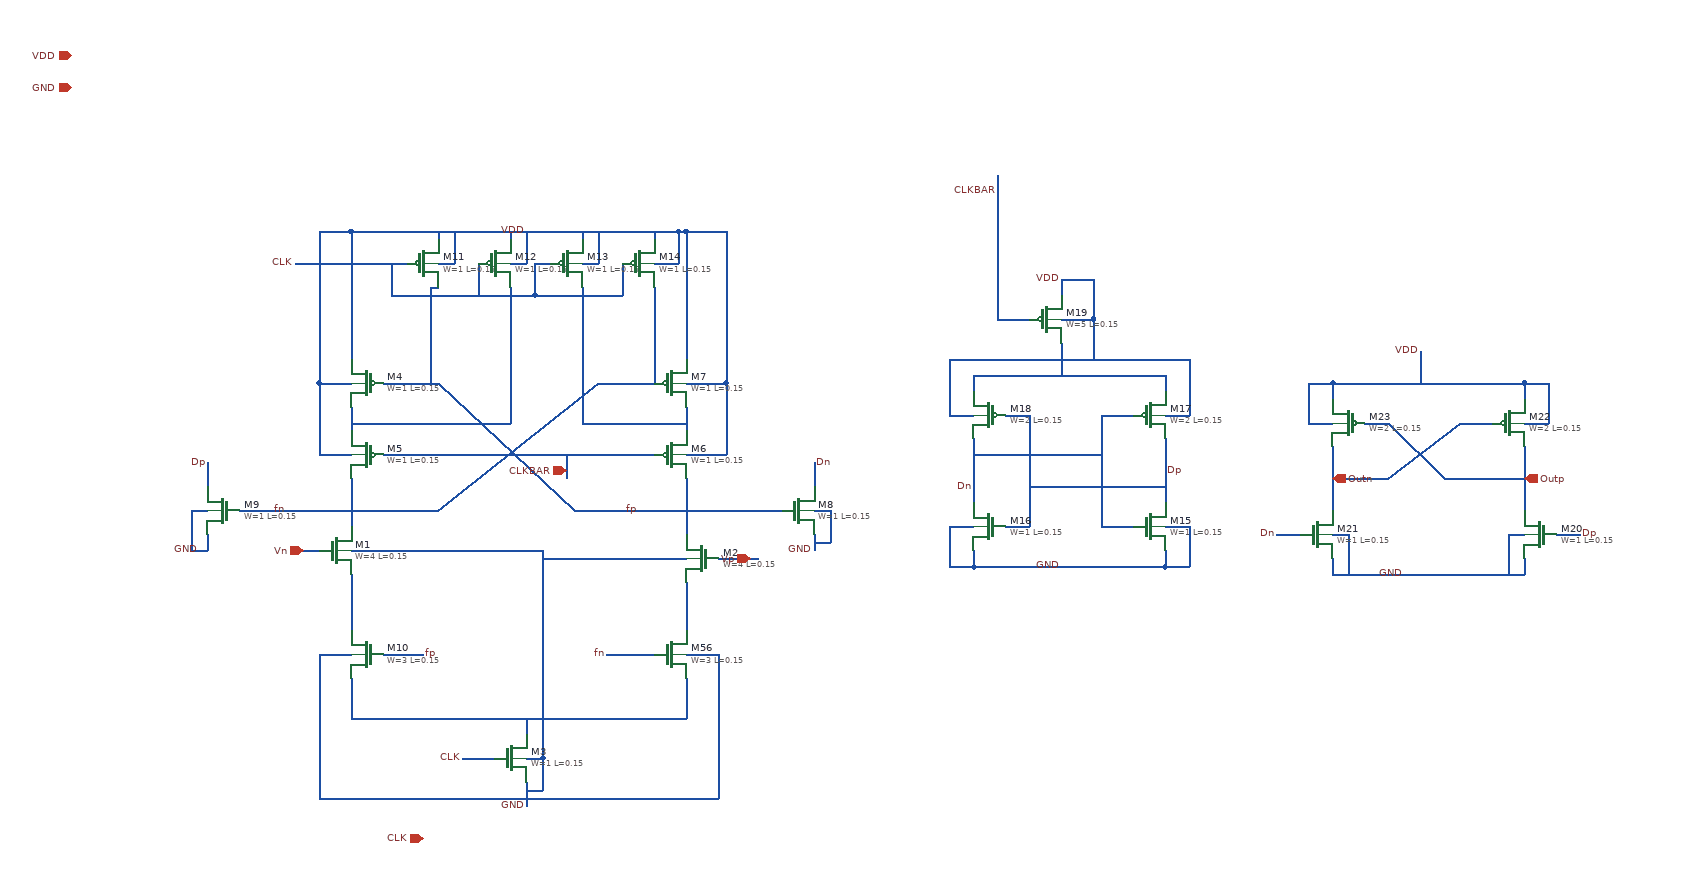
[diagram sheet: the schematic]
v {xschem version=3.0.0 file_version=1.2 }
G {}
K {}
V {}
S {}
E {}
N 1370 -860 1370 -820 {
lab=#net1}
N 1370 -680 1790 -680 {
lab=#net2}
N 1790 -850 1790 -820 {
lab=#net3}
N 1590 -680 1590 -660 {
lab=#net2}
N 1590 -600 1590 -570 {
lab=GND}
N 1590 -630 1610 -630 {
lab=GND}
N 1610 -630 1610 -590 {
lab=GND}
N 1590 -590 1610 -590 {
lab=GND}
N 1370 -890 1560 -890 {
lab=GND}
N 1610 -880 1790 -880 {
lab=GND}
N 1170 -940 1190 -940 {
lab=GND}
N 1170 -940 1170 -890 {
lab=GND}
N 1170 -890 1190 -890 {
lab=GND}
N 1190 -910 1190 -890 {
lab=GND}
N 1190 -1000 1190 -970 {
lab=Dp}
N 1340 -1250 1380 -1250 {
lab=CLK}
N 1530 -1250 1530 -1210 {
lab=CLK}
N 1420 -1250 1420 -1210 {
lab=CLK}
N 1600 -1250 1620 -1250 {
lab=CLK}
N 1600 -1250 1600 -1210 {
lab=CLK}
N 1480 -1210 1600 -1210 {
lab=CLK}
N 1600 -1210 1710 -1210 {
lab=CLK}
N 1420 -1290 1440 -1290 {
lab=VDD}
N 1440 -1290 1760 -1290 {
lab=VDD}
N 1660 -1290 1660 -1280 {
lab=VDD}
N 1570 -1290 1570 -1280 {
lab=VDD}
N 1570 -1250 1580 -1250 {
lab=VDD}
N 1580 -1250 1590 -1250 {
lab=VDD}
N 1590 -1290 1590 -1250 {
lab=VDD}
N 1660 -1250 1680 -1250 {
lab=VDD}
N 1680 -1290 1680 -1250 {
lab=VDD}
N 1760 -1250 1780 -1250 {
lab=VDD}
N 1780 -1290 1780 -1250 {
lab=VDD}
N 1760 -1290 1780 -1290 {
lab=VDD}
N 1510 -630 1550 -630 {
lab=CLK}
N 1300 -890 1330 -890 {
lab=Vn}
N 1830 -880 1880 -880 {
lab=Vp}
N 2190 -1060 2220 -1060 {
lab=Dp}
N 2220 -1060 2220 -920 {
lab=Dp}
N 2190 -920 2220 -920 {
lab=Dp}
N 2310 -1060 2350 -1060 {
lab=Dn}
N 2310 -1060 2310 -920 {
lab=Dn}
N 2150 -1030 2150 -950 {
lab=Dn}
N 2310 -920 2350 -920 {
lab=Dn}
N 2390 -1030 2390 -950 {
lab=Dp}
N 2150 -890 2150 -870 {
lab=GND}
N 2150 -870 2390 -870 {
lab=GND}
N 2390 -890 2390 -870 {
lab=GND}
N 2150 -1110 2150 -1090 {
lab=#net4}
N 2150 -1110 2390 -1110 {
lab=#net4}
N 2390 -1110 2390 -1090 {
lab=#net4}
N 2150 -1010 2310 -1010 {
lab=Dn}
N 2220 -970 2390 -970 {
lab=Dp}
N 2120 -920 2150 -920 {
lab=GND}
N 2120 -920 2120 -870 {
lab=GND}
N 2120 -870 2150 -870 {
lab=GND}
N 2390 -920 2410 -920 {
lab=GND}
N 2410 -920 2420 -920 {
lab=GND}
N 2420 -920 2420 -870 {
lab=GND}
N 2390 -870 2420 -870 {
lab=GND}
N 2260 -1150 2260 -1110 {
lab=#net4}
N 2260 -1180 2300 -1180 {
lab=VDD}
N 2300 -1230 2300 -1180 {
lab=VDD}
N 2260 -1230 2300 -1230 {
lab=VDD}
N 2260 -1230 2260 -1210 {
lab=VDD}
N 2120 -1060 2150 -1060 {
lab=VDD}
N 2120 -1110 2120 -1060 {
lab=VDD}
N 2390 -1060 2420 -1060 {
lab=VDD}
N 2420 -1110 2420 -1060 {
lab=VDD}
N 2190 -1180 2220 -1180 {
lab=CLKBAR}
N 2640 -1050 2670 -1050 {
lab=Outp}
N 2760 -1050 2800 -1050 {
lab=Outp}
N 2600 -1020 2600 -940 {
lab=Outp}
N 2840 -1020 2840 -940 {
lab=Outp}
N 2600 -880 2600 -860 {
lab=GND}
N 2600 -860 2840 -860 {
lab=GND}
N 2840 -880 2840 -860 {
lab=GND}
N 2600 -1100 2600 -1080 {
lab=VDD}
N 2600 -1100 2840 -1100 {
lab=VDD}
N 2840 -1100 2840 -1080 {
lab=VDD}
N 2710 -1140 2710 -1100 {
lab=VDD}
N 2570 -1050 2600 -1050 {
lab=VDD}
N 2570 -1100 2570 -1050 {
lab=VDD}
N 2570 -1100 2600 -1100 {
lab=VDD}
N 2840 -1050 2870 -1050 {
lab=VDD}
N 2870 -1100 2870 -1050 {
lab=VDD}
N 2840 -1100 2870 -1100 {
lab=VDD}
N 2530 -910 2560 -910 {
lab=Dn}
N 2880 -910 2910 -910 {
lab=Dp}
N 2670 -1050 2740 -980 {
lab=Outp}
N 2740 -980 2840 -980 {
lab=Outp}
N 2670 -980 2760 -1050 {
lab=Outp}
N 2600 -980 2670 -980 {
lab=Outp}
N 2600 -910 2620 -910 {
lab=GND}
N 2620 -910 2620 -860 {
lab=GND}
N 2820 -910 2840 -910 {
lab=GND}
N 2820 -910 2820 -860 {
lab=GND}
N 2120 -1130 2120 -1110 {
lab=VDD}
N 2120 -1130 2420 -1130 {
lab=VDD}
N 2420 -1130 2420 -1110 {
lab=VDD}
N 2300 -1180 2300 -1130 {
lab=VDD}
N 2180 -1360 2180 -1180 {
lab=CLKBAR}
N 2180 -1180 2190 -1180 {
lab=CLKBAR}
N 1610 -880 1610 -770 {
lab=GND}
N 1560 -890 1610 -890 {
lab=GND}
N 1610 -890 1610 -870 {
lab=GND}
N 1370 -980 1370 -920 {
lab=fn}
N 1370 -1070 1370 -1040 {
lab=#net5}
N 1790 -980 1790 -910 {
lab=fp}
N 1790 -1070 1790 -1040 {
lab=#net6}
N 1370 -1150 1370 -1130 {
lab=VDD}
N 1790 -1150 1790 -1130 {
lab=VDD}
N 1410 -1010 1750 -1010 {
lab=CLKBAR}
N 1410 -1100 1480 -1100 {
lab=fp}
N 1480 -1100 1650 -940 {
lab=fp}
N 1650 -940 1790 -940 {
lab=fp}
N 1680 -1100 1750 -1100 {
lab=fn}
N 1480 -940 1680 -1100 {
lab=fn}
N 1370 -940 1480 -940 {
lab=fn}
N 1370 -1160 1370 -1150 {
lab=VDD}
N 1790 -1160 1790 -1150 {
lab=VDD}
N 1750 -1290 1750 -1280 {
lab=VDD}
N 1750 -1250 1760 -1250 {
lab=VDD}
N 1710 -1250 1710 -1210 {
lab=CLK}
N 1750 -1220 1750 -1100 {
lab=fn}
N 1370 -1050 1520 -1050 {
lab=#net5}
N 1570 -1220 1570 -1050 {
lab=#net5}
N 1660 -1220 1660 -1050 {
lab=#net6}
N 1660 -1050 1790 -1050 {
lab=#net6}
N 1230 -940 1370 -940 {
lab=fn}
N 1950 -910 1950 -890 {
lab=GND}
N 1950 -940 1970 -940 {
lab=GND}
N 1970 -940 1970 -900 {
lab=GND}
N 1950 -900 1970 -900 {
lab=GND}
N 1950 -990 1950 -970 {
lab=Dn}
N 1950 -1000 1950 -990 {
lab=Dn}
N 1790 -940 1910 -940 {
lab=fp}
N 1520 -1050 1570 -1050 {
lab=#net5}
N 1430 -1250 1440 -1250 {
lab=CLK}
N 1380 -1250 1430 -1250 {
lab=CLK}
N 1420 -1210 1480 -1210 {
lab=CLK}
N 1370 -1290 1370 -1160 {
lab=VDD}
N 1370 -1290 1420 -1290 {
lab=VDD}
N 1790 -1290 1790 -1160 {
lab=VDD}
N 1780 -1290 1790 -1290 {
lab=VDD}
N 1480 -1290 1480 -1280 {
lab=VDD}
N 1480 -1250 1500 -1250 {
lab=VDD}
N 1500 -1290 1500 -1250 {
lab=VDD}
N 1610 -770 1610 -630 {
lab=GND}
N 1370 -730 1370 -680 {
lab=#net2}
N 1790 -730 1790 -680 {
lab=#net2}
N 1370 -820 1370 -790 {
lab=#net1}
N 1790 -820 1790 -790 {
lab=#net3}
N 1410 -760 1460 -760 {
lab=fp}
N 1690 -760 1750 -760 {
lab=fn}
N 1790 -1010 1840 -1010 {
lab=VDD}
N 1840 -1100 1840 -1010 {
lab=VDD}
N 1790 -1100 1840 -1100 {
lab=VDD}
N 1840 -1290 1840 -1100 {
lab=VDD}
N 1790 -1290 1840 -1290 {
lab=VDD}
N 1330 -1010 1370 -1010 {
lab=VDD}
N 1330 -1100 1330 -1010 {
lab=VDD}
N 1330 -1100 1370 -1100 {
lab=VDD}
N 1330 -1290 1330 -1100 {
lab=VDD}
N 1330 -1290 1370 -1290 {
lab=VDD}
N 1330 -760 1370 -760 {
lab=GND}
N 1330 -760 1330 -590 {
lab=GND}
N 1330 -590 1330 -580 {
lab=GND}
N 1330 -580 1590 -580 {
lab=GND}
N 1590 -580 1830 -580 {
lab=GND}
N 1830 -760 1830 -580 {
lab=GND}
N 1790 -760 1830 -760 {
lab=GND}
N 1470 -1220 1480 -1220 {
lab=fp}
N 1470 -1220 1470 -1200 {
lab=fp}
N 1470 -1200 1470 -1100 {
lab=fp}
N 1640 -1010 1640 -980 {
lab=CLKBAR}
N 1300 -1250 1340 -1250 {
lab=CLK}
C {sky130_fd_pr/nfet_01v8.sym} 1350 -890 0 0 {name=M1
L=0.15
W=4
nf=1 
mult=1
ad="'int((nf+1)/2) * W/nf * 0.29'" 
pd="'2*int((nf+1)/2) * (W/nf + 0.29)'"
as="'int((nf+2)/2) * W/nf * 0.29'" 
ps="'2*int((nf+2)/2) * (W/nf + 0.29)'"
nrd="'0.29 / W'" nrs="'0.29 / W'"
sa=0 sb=0 sd=0
model=nfet_01v8
spiceprefix=X
}
C {sky130_fd_pr/nfet_01v8.sym} 1810 -880 0 1 {name=M2
L=0.15
W=4
nf=1 
mult=1
ad="'int((nf+1)/2) * W/nf * 0.29'" 
pd="'2*int((nf+1)/2) * (W/nf + 0.29)'"
as="'int((nf+2)/2) * W/nf * 0.29'" 
ps="'2*int((nf+2)/2) * (W/nf + 0.29)'"
nrd="'0.29 / W'" nrs="'0.29 / W'"
sa=0 sb=0 sd=0
model=nfet_01v8
spiceprefix=X
}
C {sky130_fd_pr/nfet_01v8.sym} 1570 -630 0 0 {name=M3
L=0.15
W=1
nf=1 
mult=1
ad="'int((nf+1)/2) * W/nf * 0.29'" 
pd="'2*int((nf+1)/2) * (W/nf + 0.29)'"
as="'int((nf+2)/2) * W/nf * 0.29'" 
ps="'2*int((nf+2)/2) * (W/nf + 0.29)'"
nrd="'0.29 / W'" nrs="'0.29 / W'"
sa=0 sb=0 sd=0
model=nfet_01v8
spiceprefix=X
}
C {sky130_fd_pr/nfet_01v8.sym} 1210 -940 0 1 {name=M9
L=0.15
W=1
nf=1 
mult=1
ad="'int((nf+1)/2) * W/nf * 0.29'" 
pd="'2*int((nf+1)/2) * (W/nf + 0.29)'"
as="'int((nf+2)/2) * W/nf * 0.29'" 
ps="'2*int((nf+2)/2) * (W/nf + 0.29)'"
nrd="'0.29 / W'" nrs="'0.29 / W'"
sa=0 sb=0 sd=0
model=nfet_01v8
spiceprefix=X
}
C {sky130_fd_pr/pfet_01v8.sym} 1460 -1250 0 0 {name=M11
L=0.15
W=1
nf=1
mult=1
ad="'int((nf+1)/2) * W/nf * 0.29'" 
pd="'2*int((nf+1)/2) * (W/nf + 0.29)'"
as="'int((nf+2)/2) * W/nf * 0.29'" 
ps="'2*int((nf+2)/2) * (W/nf + 0.29)'"
nrd="'0.29 / W'" nrs="'0.29 / W'"
sa=0 sb=0 sd=0
model=pfet_01v8
spiceprefix=X
}
C {sky130_fd_pr/pfet_01v8.sym} 1550 -1250 0 0 {name=M12
L=0.15
W=1
nf=1
mult=1
ad="'int((nf+1)/2) * W/nf * 0.29'" 
pd="'2*int((nf+1)/2) * (W/nf + 0.29)'"
as="'int((nf+2)/2) * W/nf * 0.29'" 
ps="'2*int((nf+2)/2) * (W/nf + 0.29)'"
nrd="'0.29 / W'" nrs="'0.29 / W'"
sa=0 sb=0 sd=0
model=pfet_01v8
spiceprefix=X
}
C {sky130_fd_pr/pfet_01v8.sym} 1640 -1250 0 0 {name=M13
L=0.15
W=1
nf=1
mult=1
ad="'int((nf+1)/2) * W/nf * 0.29'" 
pd="'2*int((nf+1)/2) * (W/nf + 0.29)'"
as="'int((nf+2)/2) * W/nf * 0.29'" 
ps="'2*int((nf+2)/2) * (W/nf + 0.29)'"
nrd="'0.29 / W'" nrs="'0.29 / W'"
sa=0 sb=0 sd=0
model=pfet_01v8
spiceprefix=X
}
C {sky130_fd_pr/pfet_01v8.sym} 1730 -1250 0 0 {name=M14
L=0.15
W=1
nf=1
mult=1
ad="'int((nf+1)/2) * W/nf * 0.29'" 
pd="'2*int((nf+1)/2) * (W/nf + 0.29)'"
as="'int((nf+2)/2) * W/nf * 0.29'" 
ps="'2*int((nf+2)/2) * (W/nf + 0.29)'"
nrd="'0.29 / W'" nrs="'0.29 / W'"
sa=0 sb=0 sd=0
model=pfet_01v8
spiceprefix=X
}
C {sky130_fd_pr/nfet_01v8.sym} 2370 -920 0 0 {name=M15
L=0.15
W=1
nf=1 
mult=1
ad="'int((nf+1)/2) * W/nf * 0.29'" 
pd="'2*int((nf+1)/2) * (W/nf + 0.29)'"
as="'int((nf+2)/2) * W/nf * 0.29'" 
ps="'2*int((nf+2)/2) * (W/nf + 0.29)'"
nrd="'0.29 / W'" nrs="'0.29 / W'"
sa=0 sb=0 sd=0
model=nfet_01v8
spiceprefix=X
}
C {sky130_fd_pr/nfet_01v8.sym} 2170 -920 0 1 {name=M16
L=0.15
W=1
nf=1 
mult=1
ad="'int((nf+1)/2) * W/nf * 0.29'" 
pd="'2*int((nf+1)/2) * (W/nf + 0.29)'"
as="'int((nf+2)/2) * W/nf * 0.29'" 
ps="'2*int((nf+2)/2) * (W/nf + 0.29)'"
nrd="'0.29 / W'" nrs="'0.29 / W'"
sa=0 sb=0 sd=0
model=nfet_01v8
spiceprefix=X
}
C {sky130_fd_pr/pfet_01v8.sym} 2370 -1060 0 0 {name=M17
L=0.15
W=2
nf=1
mult=1
ad="'int((nf+1)/2) * W/nf * 0.29'" 
pd="'2*int((nf+1)/2) * (W/nf + 0.29)'"
as="'int((nf+2)/2) * W/nf * 0.29'" 
ps="'2*int((nf+2)/2) * (W/nf + 0.29)'"
nrd="'0.29 / W'" nrs="'0.29 / W'"
sa=0 sb=0 sd=0
model=pfet_01v8
spiceprefix=X
}
C {sky130_fd_pr/pfet_01v8.sym} 2170 -1060 0 1 {name=M18
L=0.15
W=2
nf=1
mult=1
ad="'int((nf+1)/2) * W/nf * 0.29'" 
pd="'2*int((nf+1)/2) * (W/nf + 0.29)'"
as="'int((nf+2)/2) * W/nf * 0.29'" 
ps="'2*int((nf+2)/2) * (W/nf + 0.29)'"
nrd="'0.29 / W'" nrs="'0.29 / W'"
sa=0 sb=0 sd=0
model=pfet_01v8
spiceprefix=X
}
C {sky130_fd_pr/pfet_01v8.sym} 2240 -1180 0 0 {name=M19
L=0.15
W=5
nf=1
mult=1
ad="'int((nf+1)/2) * W/nf * 0.29'" 
pd="'2*int((nf+1)/2) * (W/nf + 0.29)'"
as="'int((nf+2)/2) * W/nf * 0.29'" 
ps="'2*int((nf+2)/2) * (W/nf + 0.29)'"
nrd="'0.29 / W'" nrs="'0.29 / W'"
sa=0 sb=0 sd=0
model=pfet_01v8
spiceprefix=X
}
C {devices/lab_pin.sym} 1190 -1000 0 0 {name=l12 sig_type=std_logic lab=Dp}
C {devices/lab_pin.sym} 2150 -970 0 0 {name=l14 sig_type=std_logic lab=Dn}
C {devices/lab_pin.sym} 2390 -990 2 0 {name=l15 sig_type=std_logic lab=Dp}
C {sky130_fd_pr/nfet_01v8.sym} 2860 -910 0 1 {name=M20
L=0.15
W=1
nf=1 
mult=1
ad="'int((nf+1)/2) * W/nf * 0.29'" 
pd="'2*int((nf+1)/2) * (W/nf + 0.29)'"
as="'int((nf+2)/2) * W/nf * 0.29'" 
ps="'2*int((nf+2)/2) * (W/nf + 0.29)'"
nrd="'0.29 / W'" nrs="'0.29 / W'"
sa=0 sb=0 sd=0
model=nfet_01v8
spiceprefix=X
}
C {sky130_fd_pr/nfet_01v8.sym} 2580 -910 0 0 {name=M21
L=0.15
W=1
nf=1 
mult=1
ad="'int((nf+1)/2) * W/nf * 0.29'" 
pd="'2*int((nf+1)/2) * (W/nf + 0.29)'"
as="'int((nf+2)/2) * W/nf * 0.29'" 
ps="'2*int((nf+2)/2) * (W/nf + 0.29)'"
nrd="'0.29 / W'" nrs="'0.29 / W'"
sa=0 sb=0 sd=0
model=nfet_01v8
spiceprefix=X
}
C {sky130_fd_pr/pfet_01v8.sym} 2820 -1050 0 0 {name=M22
L=0.15
W=2
nf=1
mult=1
ad="'int((nf+1)/2) * W/nf * 0.29'" 
pd="'2*int((nf+1)/2) * (W/nf + 0.29)'"
as="'int((nf+2)/2) * W/nf * 0.29'" 
ps="'2*int((nf+2)/2) * (W/nf + 0.29)'"
nrd="'0.29 / W'" nrs="'0.29 / W'"
sa=0 sb=0 sd=0
model=pfet_01v8
spiceprefix=X
}
C {sky130_fd_pr/pfet_01v8.sym} 2620 -1050 0 1 {name=M23
L=0.15
W=2
nf=1
mult=1
ad="'int((nf+1)/2) * W/nf * 0.29'" 
pd="'2*int((nf+1)/2) * (W/nf + 0.29)'"
as="'int((nf+2)/2) * W/nf * 0.29'" 
ps="'2*int((nf+2)/2) * (W/nf + 0.29)'"
nrd="'0.29 / W'" nrs="'0.29 / W'"
sa=0 sb=0 sd=0
model=pfet_01v8
spiceprefix=X
}
C {devices/iopin.sym} 1020 -1510 0 0 {name=p1 lab=VDD}
C {devices/iopin.sym} 1020 -1470 0 0 {name=p2 lab=GND
}
C {devices/ipin.sym} 1870 -880 2 0 {name=p3 lab=Vp
}
C {devices/ipin.sym} 1310 -890 0 0 {name=p4 lab=Vn}
C {devices/iopin.sym} 1460 -530 2 0 {name=p5 lab=CLK}
C {devices/opin.sym} 2840 -980 0 0 {name=p7 lab=Outp}
C {devices/opin.sym} 2600 -980 2 0 {name=p8 lab=Outn}
C {devices/lab_pin.sym} 1590 -1290 1 0 {name=l9 sig_type=std_logic lab=VDD}
C {devices/lab_pin.sym} 2260 -1230 1 0 {name=l11 sig_type=std_logic lab=VDD}
C {devices/lab_pin.sym} 2710 -1140 1 0 {name=l27 sig_type=std_logic lab=VDD}
C {devices/lab_pin.sym} 1590 -570 3 0 {name=l10 sig_type=std_logic lab=GND}
C {devices/lab_pin.sym} 2260 -870 3 0 {name=l2 sig_type=std_logic lab=GND}
C {devices/lab_pin.sym} 2690 -860 3 0 {name=l19 sig_type=std_logic lab=GND}
C {devices/lab_pin.sym} 1180 -890 3 0 {name=l3 sig_type=std_logic lab=GND}
C {devices/lab_wire.sym} 2180 -1340 0 0 {name=l28 sig_type=std_logic lab=CLKBAR}
C {devices/iopin.sym} 1640 -990 1 0 {name=p9 lab=CLKBAR}
C {sky130_fd_pr/pfet_01v8.sym} 1390 -1100 0 1 {name=M4
L=0.15
W=1
nf=1
mult=1
ad="'int((nf+1)/2) * W/nf * 0.29'" 
pd="'2*int((nf+1)/2) * (W/nf + 0.29)'"
as="'int((nf+2)/2) * W/nf * 0.29'" 
ps="'2*int((nf+2)/2) * (W/nf + 0.29)'"
nrd="'0.29 / W'" nrs="'0.29 / W'"
sa=0 sb=0 sd=0
model=pfet_01v8
spiceprefix=X
}
C {sky130_fd_pr/pfet_01v8.sym} 1390 -1010 0 1 {name=M5
L=0.15
W=1
nf=1
mult=1
ad="'int((nf+1)/2) * W/nf * 0.29'" 
pd="'2*int((nf+1)/2) * (W/nf + 0.29)'"
as="'int((nf+2)/2) * W/nf * 0.29'" 
ps="'2*int((nf+2)/2) * (W/nf + 0.29)'"
nrd="'0.29 / W'" nrs="'0.29 / W'"
sa=0 sb=0 sd=0
model=pfet_01v8
spiceprefix=X
}
C {sky130_fd_pr/pfet_01v8.sym} 1770 -1010 0 0 {name=M6
L=0.15
W=1
nf=1
mult=1
ad="'int((nf+1)/2) * W/nf * 0.29'" 
pd="'2*int((nf+1)/2) * (W/nf + 0.29)'"
as="'int((nf+2)/2) * W/nf * 0.29'" 
ps="'2*int((nf+2)/2) * (W/nf + 0.29)'"
nrd="'0.29 / W'" nrs="'0.29 / W'"
sa=0 sb=0 sd=0
model=pfet_01v8
spiceprefix=X
}
C {sky130_fd_pr/pfet_01v8.sym} 1770 -1100 0 0 {name=M7
L=0.15
W=1
nf=1
mult=1
ad="'int((nf+1)/2) * W/nf * 0.29'" 
pd="'2*int((nf+1)/2) * (W/nf + 0.29)'"
as="'int((nf+2)/2) * W/nf * 0.29'" 
ps="'2*int((nf+2)/2) * (W/nf + 0.29)'"
nrd="'0.29 / W'" nrs="'0.29 / W'"
sa=0 sb=0 sd=0
model=pfet_01v8
spiceprefix=X
}
C {sky130_fd_pr/nfet_01v8.sym} 1930 -940 0 0 {name=M8
L=0.15
W=1
nf=1 
mult=1
ad="'int((nf+1)/2) * W/nf * 0.29'" 
pd="'2*int((nf+1)/2) * (W/nf + 0.29)'"
as="'int((nf+2)/2) * W/nf * 0.29'" 
ps="'2*int((nf+2)/2) * (W/nf + 0.29)'"
nrd="'0.29 / W'" nrs="'0.29 / W'"
sa=0 sb=0 sd=0
model=nfet_01v8
spiceprefix=X
}
C {devices/lab_pin.sym} 1950 -1000 2 0 {name=l6 sig_type=std_logic lab=Dn}
C {devices/lab_pin.sym} 1950 -890 3 0 {name=l7 sig_type=std_logic lab=GND}
C {sky130_fd_pr/nfet_01v8.sym} 1390 -760 0 1 {name=M10
L=0.15
W=3
nf=1 
mult=1
ad="'int((nf+1)/2) * W/nf * 0.29'" 
pd="'2*int((nf+1)/2) * (W/nf + 0.29)'"
as="'int((nf+2)/2) * W/nf * 0.29'" 
ps="'2*int((nf+2)/2) * (W/nf + 0.29)'"
nrd="'0.29 / W'" nrs="'0.29 / W'"
sa=0 sb=0 sd=0
model=nfet_01v8
spiceprefix=X
}
C {sky130_fd_pr/nfet_01v8.sym} 1770 -760 0 0 {name=M56
L=0.15
W=3
nf=1 
mult=1
ad="'int((nf+1)/2) * W/nf * 0.29'" 
pd="'2*int((nf+1)/2) * (W/nf + 0.29)'"
as="'int((nf+2)/2) * W/nf * 0.29'" 
ps="'2*int((nf+2)/2) * (W/nf + 0.29)'"
nrd="'0.29 / W'" nrs="'0.29 / W'"
sa=0 sb=0 sd=0
model=nfet_01v8
spiceprefix=X
}
C {devices/lab_pin.sym} 1290 -940 0 0 {name=l13 sig_type=std_logic lab=fn}
C {devices/lab_pin.sym} 1730 -940 0 0 {name=l35 sig_type=std_logic lab=fp}
C {devices/lab_pin.sym} 1460 -760 2 0 {name=l36 sig_type=std_logic lab=fp}
C {devices/lab_pin.sym} 1690 -760 0 0 {name=l37 sig_type=std_logic lab=fn}
C {devices/lab_pin.sym} 2530 -910 0 0 {name=l30 sig_type=std_logic lab=Dn}
C {devices/lab_pin.sym} 2910 -910 2 0 {name=l31 sig_type=std_logic lab=Dp}
C {devices/lab_pin.sym} 1300 -1250 0 0 {name=l5 sig_type=std_logic lab=CLK}
C {devices/lab_pin.sym} 1510 -630 0 0 {name=l8 sig_type=std_logic lab=CLK}
